VERSION 5.8 ;
BUSBITCHARS "[]" ;
DIVIDERCHAR "/" ;

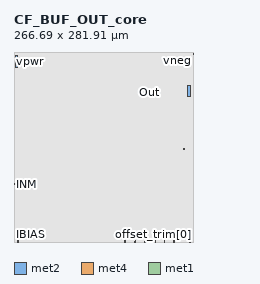
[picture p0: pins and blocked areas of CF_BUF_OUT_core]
MACRO CF_BUF_OUT_core
  CLASS BLOCK ;
  ORIGIN 0 0 ;
  FOREIGN CF_BUF_OUT_core 0 0 ;
  SIZE 266.69 BY 281.91 ;
  PIN vpb
    DIRECTION INPUT ;
    USE POWER ;
    PORT
      LAYER met2 ;
        RECT 194.365 0 195.665 1.385 ;
    END
  END vpb
  PIN Out
    DIRECTION OUTPUT ;
    USE SIGNAL ;
    PORT
      LAYER met4 ;
        RECT 197.955 219.83 205.565 224.14 ;
    END
  END Out
  PIN IBIAS
    DIRECTION INPUT ;
    USE SIGNAL ;
    PORT
      LAYER met1 ;
        RECT 5.925 0 6.155 1.575 ;
    END
  END IBIAS
  PIN vneg
    DIRECTION INPUT ;
    USE SIGNAL ;
    PORT
      LAYER met1 ;
        RECT 266.29 278.62 266.69 279.755 ;
    END
  END vneg
  PIN vpwr_core
    DIRECTION INOUT ;
    USE SIGNAL ;
    PORT
      LAYER met1 ;
        RECT 195.905 0 196.82 4.62 ;
    END
  END vpwr_core
  PIN vgnd
    DIRECTION INPUT ;
    USE GROUND ;
    PORT
      LAYER met2 ;
        RECT 252.15 137.395 252.78 138.33 ;
        RECT 256.725 215.47 261.92 231.99 ;
    END
  END vgnd
  PIN vpwr
    DIRECTION INPUT ;
    USE POWER ;
    PORT
      LAYER met2 ;
        RECT 2.145 258.92 5.85 277.275 ;
    END
  END vpwr
  PIN vnb
    DIRECTION INPUT ;
    USE GROUND ;
    PORT
      LAYER met2 ;
        RECT 178.26 0 179.58 1.43 ;
    END
  END vnb
  PIN INM
    DIRECTION INPUT ;
    USE SIGNAL ;
    PORT
      LAYER met2 ;
        RECT 0 85.38 3.25 85.765 ;
    END
  END INM
  PIN INP
    DIRECTION INPUT ;
    USE SIGNAL ;
    PORT
      LAYER met2 ;
        RECT 0 86.375 3.25 86.76 ;
    END
  END INP
  PIN offset_trim[0]
    DIRECTION INPUT ;
    USE SIGNAL ;
    PORT
      LAYER met2 ;
        RECT 210.155 0 210.355 2.045 ;
    END
  END offset_trim[0]
  PIN offset_trim[1]
    DIRECTION INPUT ;
    USE SIGNAL ;
    PORT
      LAYER met2 ;
        RECT 223.58 0 223.78 2.045 ;
    END
  END offset_trim[1]
  PIN offset_trim[2]
    DIRECTION INPUT ;
    USE SIGNAL ;
    PORT
      LAYER met2 ;
        RECT 237.28 0 237.48 2.045 ;
    END
  END offset_trim[2]
  PIN offset_trim[3]
    DIRECTION INPUT ;
    USE SIGNAL ;
    PORT
      LAYER met2 ;
        RECT 180.74 0 180.94 2.05 ;
    END
  END offset_trim[3]
  PIN offset_trim[4]
    DIRECTION INPUT ;
    USE SIGNAL ;
    PORT
      LAYER met2 ;
        RECT 164.565 0 164.765 2.045 ;
    END
  END offset_trim[4]
  PIN pd
    DIRECTION INPUT ;
    USE SIGNAL ;
    PORT
      LAYER met2 ;
        RECT 260.04 0 260.24 2.045 ;
    END
  END pd
  PIN enable_hv
    DIRECTION INPUT ;
    USE SIGNAL ;
    PORT
      LAYER met2 ;
        RECT 260.52 0 260.72 2.045 ;
    END
  END enable_hv
  PIN pwr_modes[1]
    DIRECTION INPUT ;
    USE SIGNAL ;
    PORT
      LAYER met2 ;
        RECT 261.03 0 261.23 2.045 ;
    END
  END pwr_modes[1]
  PIN pwr_modes[0]
    DIRECTION INPUT ;
    USE SIGNAL ;
    PORT
      LAYER met2 ;
        RECT 261.54 0 261.74 2.045 ;
    END
  END pwr_modes[0]
  OBS
    LAYER li1 ;
      RECT 0 0 266.69 281.91 ;
    LAYER met1 ;
      RECT 0 0 5.925 281.91 ;
      RECT 5.925 1.575 6.155 281.91 ;
      RECT 6.155 0 195.905 281.91 ;
      RECT 195.905 4.62 196.82 281.91 ;
      RECT 196.82 0 266.29 281.91 ;
      RECT 266.29 0 266.69 278.62 ;
      RECT 266.29 279.755 266.69 281.91 ;
    LAYER met2 ;
      RECT 0 0 2.145 85.38 ;
      RECT 0 85.765 2.145 86.375 ;
      RECT 0 86.76 2.145 281.91 ;
      RECT 2.145 0 3.25 85.38 ;
      RECT 2.145 85.765 3.25 86.375 ;
      RECT 2.145 86.76 3.25 258.92 ;
      RECT 2.145 277.275 3.25 281.91 ;
      RECT 3.25 0 5.85 258.92 ;
      RECT 3.25 277.275 5.85 281.91 ;
      RECT 5.85 0 164.565 281.91 ;
      RECT 164.565 2.045 164.765 281.91 ;
      RECT 164.765 0 178.26 281.91 ;
      RECT 178.26 1.43 179.58 281.91 ;
      RECT 179.58 0 180.74 281.91 ;
      RECT 180.74 2.05 180.94 281.91 ;
      RECT 180.94 0 194.365 281.91 ;
      RECT 194.365 1.385 195.665 281.91 ;
      RECT 195.665 0 210.155 281.91 ;
      RECT 210.155 2.045 210.355 281.91 ;
      RECT 210.355 0 223.58 281.91 ;
      RECT 223.58 2.045 223.78 281.91 ;
      RECT 223.78 0 237.28 281.91 ;
      RECT 237.28 2.045 237.48 281.91 ;
      RECT 237.48 0 252.15 281.91 ;
      RECT 252.15 0 252.78 137.395 ;
      RECT 252.15 138.33 252.78 281.91 ;
      RECT 252.78 0 256.725 281.91 ;
      RECT 256.725 0 260.04 215.47 ;
      RECT 256.725 231.99 260.04 281.91 ;
      RECT 260.04 2.045 260.24 215.47 ;
      RECT 260.04 231.99 260.24 281.91 ;
      RECT 260.24 0 260.52 215.47 ;
      RECT 260.24 231.99 260.52 281.91 ;
      RECT 260.52 2.045 260.72 215.47 ;
      RECT 260.52 231.99 260.72 281.91 ;
      RECT 260.72 0 261.03 215.47 ;
      RECT 260.72 231.99 261.03 281.91 ;
      RECT 261.03 2.045 261.23 215.47 ;
      RECT 261.03 231.99 261.23 281.91 ;
      RECT 261.23 0 261.54 215.47 ;
      RECT 261.23 231.99 261.54 281.91 ;
      RECT 261.54 2.045 261.74 215.47 ;
      RECT 261.54 231.99 261.74 281.91 ;
      RECT 261.74 0 261.92 215.47 ;
      RECT 261.74 231.99 261.92 281.91 ;
      RECT 261.92 0 266.69 281.91 ;
    LAYER met3 ;
      RECT 0 0 266.69 281.91 ;
    LAYER met4 ;
      RECT 0 0 197.955 281.91 ;
      RECT 197.955 0 205.565 219.83 ;
      RECT 197.955 224.14 205.565 281.91 ;
      RECT 205.565 0 266.69 281.91 ;
    LAYER met5 ;
      RECT 0 0 266.69 281.91 ;
  END
END CF_BUF_OUT_core

END LIBRARY
